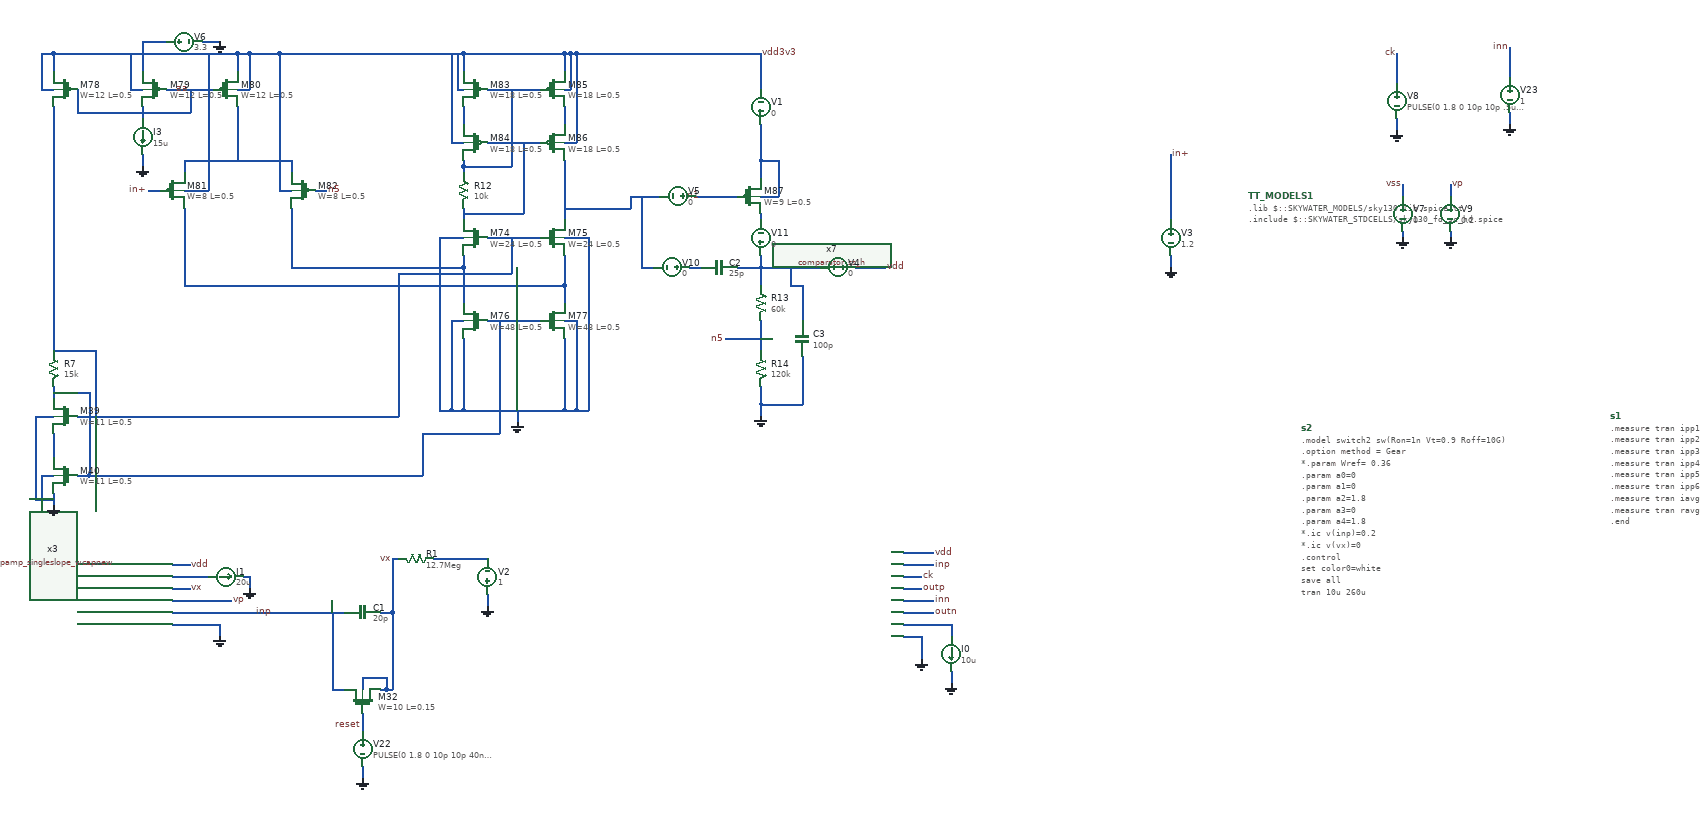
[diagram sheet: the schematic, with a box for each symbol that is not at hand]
v {xschem version=3.0.0 file_version=1.2 }
G {}
K {}
V {}
S {}
E {}
N 2980 -3130 2980 -3120 {
lab=GND}
N 2980 -3210 2980 -3190 {
lab=vp}
N 2900 -3130 2900 -3120 {
lab=GND}
N 2900 -3210 2900 -3190 {
lab=vss}
N 1180 -2490 1200 -2490 {
lab=vx}
N 1040 -2490 1120 -2490 {
lab=inp}
N 1100 -2360 1120 -2360 {
lab=inp}
N 1100 -2490 1100 -2360 {
lab=inp}
N 1180 -2360 1190 -2360 {
lab=vx}
N 1190 -2360 1200 -2360 {
lab=vx}
N 1200 -2490 1200 -2360 {
lab=vx}
N 1150 -2380 1150 -2360 {
lab=vx}
N 1150 -2380 1190 -2380 {
lab=vx}
N 1190 -2380 1190 -2360 {
lab=vx}
N 1150 -2320 1150 -2290 {
lab=reset}
N 1150 -2230 1150 -2210 {
lab=GND}
N 940 -2490 1040 -2490 {
lab=inp}
N 830 -2570 860 -2570 {
lab=vdd}
N 830 -2530 860 -2530 {
lab=vx}
N 830 -2510 910 -2510 {
lab=vp}
N 830 -2490 850 -2490 {
lab=inp}
N 830 -2470 910 -2470 {
lab=GND}
N 910 -2470 910 -2450 {
lab=GND}
N 850 -2490 940 -2490 {
lab=inp}
N 910 -2510 930 -2510 {
lab=vp}
N 960 -2550 960 -2530 {
lab=GND}
N 830 -2550 890 -2550 {
lab=#net1}
N 950 -2550 960 -2550 {
lab=GND}
N 2090 -2450 2090 -2410 {
lab=GND}
N 2060 -2570 2110 -2570 {
lab=inp}
N 2060 -2510 2110 -2510 {
lab=inn}
N 2060 -2490 2110 -2490 {
lab=outn}
N 2060 -2550 2090 -2550 {
lab=ck}
N 2060 -2530 2090 -2530 {
lab=outp}
N 2060 -2590 2110 -2590 {
lab=vdd}
N 2060 -2450 2090 -2450 {
lab=GND}
N 2140 -2470 2140 -2450 {
lab=#net2}
N 2140 -2390 2140 -2370 {
lab=GND}
N 2060 -2470 2140 -2470 {
lab=#net2}
N 2890 -3320 2890 -3300 {
lab=GND}
N 2890 -3430 2890 -3380 {
lab=ck}
N 3080 -3330 3080 -3310 {
lab=GND}
N 3080 -3440 3080 -3390 {
lab=inn}
N 2510 -3170 2510 -3150 {
lab=in+}
N 2510 -3090 2510 -3070 {
lab=GND}
N 2510 -3180 2510 -3170 {
lab=in+}
N 2510 -3190 2510 -3180 {
lab=in+}
N 2510 -3260 2510 -3250 {
lab=in+}
N 2510 -3250 2510 -3190 {
lab=in+}
N 850 -3250 850 -3230 {
lab=#net3}
N 850 -3250 1030 -3250 {
lab=#net3}
N 1030 -3250 1030 -3230 {
lab=#net3}
N 790 -3200 810 -3200 {
lab=in+}
N 1070 -3200 1090 -3200 {
lab=n5}
N 1030 -3170 1030 -3120 {
lab=#net4}
N 850 -3170 850 -3040 {
lab=#net5}
N 1030 -3070 1320 -3070 {
lab=#net4}
N 1030 -3120 1030 -3070 {
lab=#net4}
N 1490 -3090 1490 -3040 {
lab=#net5}
N 1360 -3280 1440 -3280 {
lab=#net6}
N 1440 -3280 1450 -3280 {
lab=#net6}
N 1320 -3090 1320 -3070 {
lab=#net4}
N 1360 -3120 1450 -3120 {
lab=#net7}
N 1360 -2980 1450 -2980 {
lab=#net8}
N 1320 -3070 1320 -3010 {
lab=#net4}
N 850 -3040 1490 -3040 {
lab=#net5}
N 1490 -3040 1490 -3010 {
lab=#net5}
N 1320 -2950 1320 -2930 {
lab=GND}
N 1320 -2830 1490 -2830 {
lab=GND}
N 1490 -2950 1490 -2930 {
lab=GND}
N 1410 -2830 1410 -2810 {
lab=GND}
N 1300 -2980 1320 -2980 {
lab=GND}
N 1300 -2980 1300 -2930 {
lab=GND}
N 1300 -2830 1320 -2830 {
lab=GND}
N 1490 -2980 1510 -2980 {
lab=GND}
N 1510 -2980 1510 -2930 {
lab=GND}
N 1490 -2830 1510 -2830 {
lab=GND}
N 1280 -3120 1320 -3120 {
lab=GND}
N 1280 -3120 1280 -2930 {
lab=GND}
N 1280 -2830 1300 -2830 {
lab=GND}
N 1490 -3120 1530 -3120 {
lab=GND}
N 1530 -3120 1530 -2930 {
lab=GND}
N 1510 -2830 1530 -2830 {
lab=GND}
N 1400 -3120 1400 -3060 {
lab=#net7}
N 1210 -3060 1400 -3060 {
lab=#net7}
N 1210 -3060 1210 -2880 {
lab=#net7}
N 1380 -2980 1380 -2890 {
lab=#net8}
N 1250 -2790 1380 -2790 {
lab=#net8}
N 630 -2870 630 -2850 {
lab=#net8}
N 630 -2790 630 -2750 {
lab=#net9}
N 630 -2690 630 -2670 {
lab=GND}
N 630 -2930 700 -2930 {
lab=#net7}
N 700 -2930 700 -2820 {
lab=#net7}
N 670 -2820 1210 -2820 {
lab=#net7}
N 1210 -2880 1210 -2820 {
lab=#net7}
N 630 -2860 690 -2860 {
lab=#net8}
N 690 -2860 690 -2720 {
lab=#net8}
N 670 -2720 690 -2720 {
lab=#net8}
N 690 -2720 1250 -2720 {
lab=#net8}
N 600 -2820 630 -2820 {
lab=GND}
N 600 -2820 600 -2680 {
lab=GND}
N 600 -2680 630 -2680 {
lab=GND}
N 610 -2720 630 -2720 {
lab=GND}
N 610 -2720 610 -2680 {
lab=GND}
N 630 -3230 630 -2930 {
lab=#net7}
N 820 -3370 900 -3370 {
lab=aa}
N 780 -3340 780 -3320 {
lab=aa}
N 780 -3260 780 -3240 {
lab=GND}
N 630 -3340 630 -3230 {
lab=#net7}
N 670 -3370 670 -3330 {
lab=aa}
N 860 -3370 860 -3330 {
lab=aa}
N 780 -3330 860 -3330 {
lab=aa}
N 670 -3330 780 -3330 {
lab=aa}
N 630 -3430 630 -3400 {
lab=vdd3v3}
N 630 -3430 940 -3430 {
lab=vdd3v3}
N 940 -3430 940 -3400 {
lab=vdd3v3}
N 780 -3430 780 -3400 {
lab=vdd3v3}
N 780 -3450 820 -3450 {
lab=vdd3v3}
N 880 -3450 900 -3450 {
lab=GND}
N 900 -3450 910 -3450 {
lab=GND}
N 760 -3370 780 -3370 {
lab=vdd3v3}
N 760 -3430 760 -3370 {
lab=vdd3v3}
N 610 -3370 630 -3370 {
lab=vdd3v3}
N 610 -3430 610 -3370 {
lab=vdd3v3}
N 610 -3430 630 -3430 {
lab=vdd3v3}
N 940 -3370 960 -3370 {
lab=vdd3v3}
N 960 -3430 960 -3370 {
lab=vdd3v3}
N 940 -3430 960 -3430 {
lab=vdd3v3}
N 850 -3200 890 -3200 {
lab=vdd3v3}
N 890 -3430 890 -3200 {
lab=vdd3v3}
N 1010 -3430 1010 -3200 {
lab=vdd3v3}
N 960 -3430 1010 -3430 {
lab=vdd3v3}
N 1360 -3370 1440 -3370 {
lab=#net10}
N 1440 -3370 1450 -3370 {
lab=#net10}
N 1320 -3430 1320 -3400 {
lab=vdd3v3}
N 1320 -3430 1490 -3430 {
lab=vdd3v3}
N 1490 -3430 1490 -3400 {
lab=vdd3v3}
N 1010 -3430 1320 -3430 {
lab=vdd3v3}
N 1320 -3340 1320 -3310 {
lab=#net11}
N 1490 -3340 1490 -3310 {
lab=#net12}
N 1320 -3250 1320 -3240 {
lab=#net10}
N 1400 -3370 1400 -3250 {
lab=#net10}
N 1320 -3240 1400 -3240 {
lab=#net10}
N 1400 -3250 1400 -3240 {
lab=#net10}
N 1320 -3240 1320 -3230 {
lab=#net10}
N 1320 -3170 1320 -3150 {
lab=#net6}
N 1310 -3370 1320 -3370 {
lab=vdd3v3}
N 1310 -3430 1310 -3370 {
lab=vdd3v3}
N 1490 -3370 1500 -3370 {
lab=vdd3v3}
N 1500 -3430 1500 -3370 {
lab=vdd3v3}
N 1490 -3430 1500 -3430 {
lab=vdd3v3}
N 1300 -3280 1320 -3280 {
lab=vdd3v3}
N 1300 -3430 1300 -3280 {
lab=vdd3v3}
N 1490 -3280 1510 -3280 {
lab=vdd3v3}
N 1510 -3430 1510 -3280 {
lab=vdd3v3}
N 1500 -3430 1510 -3430 {
lab=vdd3v3}
N 940 -3260 940 -3250 {
lab=#net3}
N 940 -3340 940 -3320 {
lab=#net3}
N 1250 -2790 1250 -2720 {
lab=#net8}
N 1380 -2890 1380 -2790 {
lab=#net8}
N 1280 -2930 1280 -2830 {
lab=GND}
N 1300 -2930 1300 -2830 {
lab=GND}
N 1510 -2930 1510 -2830 {
lab=GND}
N 1530 -2930 1530 -2830 {
lab=GND}
N 1320 -2930 1320 -2910 {
lab=GND}
N 1320 -2850 1320 -2830 {
lab=GND}
N 1010 -3200 1030 -3200 {
lab=vdd3v3}
N 1420 -3280 1420 -3160 {
lab=#net6}
N 1320 -3160 1420 -3160 {
lab=#net6}
N 1490 -2930 1490 -2910 {
lab=GND}
N 1490 -2850 1490 -2830 {
lab=GND}
N 1490 -3250 1490 -3240 {
lab=#net13}
N 1490 -3180 1490 -3150 {
lab=#net13}
N 1490 -3170 1600 -3170 {
lab=#net13}
N 1820 -2840 1820 -2820 {
lab=GND}
N 1820 -2980 1820 -2930 {
lab=n5}
N 1820 -3070 1820 -3040 {
lab=#net14}
N 1820 -3070 1920 -3070 {
lab=#net14}
N 1820 -2870 1820 -2840 {
lab=GND}
N 1760 -2950 1820 -2950 {
lab=n5}
N 1810 -3430 1820 -3430 {
lab=vdd3v3}
N 1820 -3190 1850 -3190 {
lab=#net15}
N 1850 -3250 1850 -3190 {
lab=#net15}
N 1820 -3250 1850 -3250 {
lab=#net15}
N 1720 -3190 1780 -3190 {
lab=n1}
N 1510 -3430 1810 -3430 {
lab=vdd3v3}
N 940 -3320 940 -3260 {
lab=#net3}
N 1490 -3240 1490 -3180 {
lab=#net13}
N 1320 -2910 1320 -2850 {
lab=GND}
N 1490 -2910 1490 -2850 {
lab=GND}
N 1600 -3190 1600 -3170 {
lab=#net13}
N 1600 -3190 1650 -3190 {
lab=#net13}
N 1780 -3070 1820 -3070 {
lab=#net14}
N 1700 -3070 1720 -3070 {
lab=#net16}
N 1980 -3070 2030 -3070 {
lab=vdd}
N 780 -3450 780 -3430 {
lab=vdd3v3}
N 1200 -2500 1200 -2490 {
lab=vx}
N 1360 -2520 1360 -2500 {
lab=GND}
N 1200 -2580 1200 -2500 {
lab=vx}
N 1270 -2580 1360 -2580 {
lab=#net17}
N 1200 -2580 1210 -2580 {
lab=vx}
N 1820 -3310 1820 -3250 {
lab=#net15}
N 1820 -3430 1820 -3370 {
lab=vdd3v3}
N 1710 -3190 1720 -3190 {
lab=n1}
N 1820 -3250 1820 -3220 {
lab=#net15}
N 1820 -3090 1820 -3070 {
lab=#net14}
N 1820 -3160 1820 -3150 {
lab=#net18}
N 1620 -3070 1640 -3070 {
lab=#net13}
N 1620 -3190 1620 -3070 {
lab=#net13}
N 1890 -3040 1890 -2980 {
lab=#net14}
N 1870 -3040 1890 -3040 {
lab=#net14}
N 1870 -3070 1870 -3040 {
lab=#net14}
N 1890 -2920 1890 -2840 {
lab=GND}
N 1820 -2840 1890 -2840 {
lab=GND}
C {devices/code_shown.sym} 2730 -2800 0 0 {name=s2 only_toplevel=false value="

.model switch2 sw(Ron=1n Vt=0.9 Roff=10G)
.option method = Gear
*.param Wref= 0.36
.param a0=0
.param a1=0
.param a2=1.8
.param a3=0
.param a4=1.8
*.ic v(inp)=0.2
*.ic v(vx)=0


.control
set color0=white
save all

tran 10u 260u
plot inp inn outp outn
plot inp_neg inn outp_neg outn_neg
let i_1v8 = i(v4)
let i_3v3 = i(v6)
let i_g= i(v5)
let i_miller = i(v10)
let i_s= i(v1)
let i_d = i(v11)
let zort = vdd/i(v4)
plot i_1v8 i_3v3
plot v(vdd)
plot vdd3v3
plot i_1v8
plot i_3v3
plot i_g
plot i_miller
plot i_d
plot i_s
*show all
.endc
.end
"
}
C {devices/code.sym} 2640 -3190 0 0 {name=TT_MODELS1
only_toplevel=true
format="tcleval(@value )"
value=".lib $::SKYWATER_MODELS/sky130.lib.spice tt
.include $::SKYWATER_STDCELLS/sky130_fd_sc_hd.spice
"
spice_ignore=false
place=header}
C {devices/vsource.sym} 2980 -3160 0 0 {name=V9 value=0.2}
C {devices/gnd.sym} 2980 -3120 0 1 {name=l5 lab=GND}
C {devices/vsource.sym} 2900 -3160 0 0 {name=V7 value=0}
C {devices/gnd.sym} 2900 -3120 0 1 {name=l53 lab=GND}
C {devices/lab_pin.sym} 2900 -3210 0 0 {name=l54 sig_type=std_logic lab=vss}
C {devices/lab_pin.sym} 2980 -3210 2 0 {name=l59 sig_type=std_logic lab=vp}
C {devices/capa.sym} 1150 -2490 1 0 {name=C1
m=1
value=20p
footprint=1206
device="ceramic capacitor"}
C {pdk/sky130A/libs.tech/xschem/sky130_fd_pr/nfet_01v8.sym} 1150 -2340 3 0 {name=M32
L=0.15
W=10
nf=1 
mult=2
ad="'int((nf+1)/2) * W/nf * 0.29'" 
pd="'2*int((nf+1)/2) * (W/nf + 0.29)'"
as="'int((nf+2)/2) * W/nf * 0.29'" 
ps="'2*int((nf+2)/2) * (W/nf + 0.29)'"
nrd="'0.29 / W'" nrs="'0.29 / W'"
sa=0 sb=0 sd=0
model=nfet_01v8
spiceprefix=X
}
C {devices/vsource.sym} 1150 -2260 0 0 {name=V22 value="PULSE(0 1.8 0 10p 10p 40n 256.04u)"}
C {devices/gnd.sym} 1150 -2210 0 0 {name=l81 lab=GND}
C {devices/lab_pin.sym} 860 -2570 2 0 {name=l82 sig_type=std_logic lab=vdd}
C {devices/lab_pin.sym} 1150 -2300 0 0 {name=l83 sig_type=std_logic lab=reset}
C {devices/lab_pin.sym} 860 -2530 2 0 {name=l84 sig_type=std_logic lab=vx}
C {devices/gnd.sym} 910 -2450 0 0 {name=l85 lab=GND}
C {devices/lab_pin.sym} 1000 -2490 1 0 {name=l86 sig_type=std_logic lab=inp}
C {devices/isource.sym} 920 -2550 3 0 {name=I1 value=20u}
C {devices/gnd.sym} 960 -2530 0 0 {name=l87 lab=GND}
C {design/single_slope/opamp_singleslope_wcapnew.sym} 680 -2520 0 0 {name=x3}
C {devices/lab_pin.sym} 930 -2510 0 1 {name=l88 sig_type=std_logic lab=vp}
C {devices/gnd.sym} 2090 -2410 0 0 {name=l76 lab=GND}
C {devices/lab_pin.sym} 2110 -2590 0 1 {name=l79 sig_type=std_logic lab=vdd}
C {devices/lab_pin.sym} 2090 -2550 0 1 {name=l107 sig_type=std_logic lab=ck}
C {devices/lab_pin.sym} 2110 -2570 0 1 {name=l108 sig_type=std_logic lab=inp}
C {devices/lab_pin.sym} 2110 -2510 0 1 {name=l109 sig_type=std_logic lab=inn}
C {devices/lab_pin.sym} 2090 -2530 0 1 {name=l110 sig_type=std_logic lab=outp}
C {devices/lab_pin.sym} 2110 -2490 0 1 {name=l111 sig_type=std_logic lab=outn}
C {devices/isource.sym} 2140 -2420 0 0 {name=I0 value=10u}
C {devices/gnd.sym} 2140 -2370 0 0 {name=l112 lab=GND}
C {design/single_slope/comparator_ss_h.sym} 1910 -2520 0 0 {name=x7}
C {devices/vsource.sym} 2890 -3350 0 0 {name=V8 value="PULSE(0 1.8 0 10p 10p .5u 1u)"
}
C {devices/gnd.sym} 2890 -3300 0 0 {name=l123 lab=GND}
C {devices/lab_pin.sym} 2890 -3430 0 0 {name=l124 sig_type=std_logic lab=ck}
C {devices/vsource.sym} 3080 -3360 0 0 {name=V23 value=1}
C {devices/gnd.sym} 3080 -3310 0 0 {name=l125 lab=GND}
C {devices/lab_pin.sym} 3080 -3440 0 0 {name=l126 sig_type=std_logic lab=inn}
C {devices/vsource.sym} 2510 -3120 0 0 {name=V3 value=1.2}
C {devices/gnd.sym} 2510 -3070 0 0 {name=l4 lab=GND}
C {devices/lab_pin.sym} 2510 -3260 2 0 {name=l24 sig_type=std_logic lab=in+}
C {devices/lab_pin.sym} 790 -3200 0 0 {name=l25 sig_type=std_logic lab=in+}
C {devices/gnd.sym} 1410 -2810 0 0 {name=l26 lab=GND}
C {devices/res.sym} 630 -2900 0 0 {name=R7
value=15k
footprint=1206
device=resistor
m=1}
C {devices/gnd.sym} 630 -2670 0 0 {name=l134 lab=GND}
C {devices/isource.sym} 780 -3290 0 0 {name=I3 value=15u}
C {devices/gnd.sym} 780 -3240 0 0 {name=l97 lab=GND}
C {devices/vsource.sym} 850 -3450 3 0 {name=V6 value=3.3}
C {devices/gnd.sym} 910 -3450 0 0 {name=l98 lab=GND}
C {devices/lab_pin.sym} 860 -3370 1 0 {name=l99 sig_type=std_logic lab=aa}
C {devices/res.sym} 1320 -3200 0 0 {name=R12
value=10k
footprint=1206
device=resistor
m=1}
C {pdk/sky130A/libs.tech/xschem/sky130_fd_pr/nfet_01v8.sym} 650 -2820 0 1 {name=M39
L=0.5
W=11
nf=1 
mult=1
ad="'int((nf+1)/2) * W/nf * 0.29'" 
pd="'2*int((nf+1)/2) * (W/nf + 0.29)'"
as="'int((nf+2)/2) * W/nf * 0.29'" 
ps="'2*int((nf+2)/2) * (W/nf + 0.29)'"
nrd="'0.29 / W'" nrs="'0.29 / W'"
sa=0 sb=0 sd=0
model=nfet_01v8
spiceprefix=X
}
C {pdk/sky130A/libs.tech/xschem/sky130_fd_pr/nfet_01v8.sym} 650 -2720 0 1 {name=M40
L=0.5
W=11
nf=1 
mult=1
ad="'int((nf+1)/2) * W/nf * 0.29'" 
pd="'2*int((nf+1)/2) * (W/nf + 0.29)'"
as="'int((nf+2)/2) * W/nf * 0.29'" 
ps="'2*int((nf+2)/2) * (W/nf + 0.29)'"
nrd="'0.29 / W'" nrs="'0.29 / W'"
sa=0 sb=0 sd=0
model=nfet_01v8
spiceprefix=X
}
C {pdk/sky130A/libs.tech/xschem/sky130_fd_pr/nfet_01v8.sym} 1340 -3120 0 1 {name=M74
L=0.5
W=24
nf=4
mult=1
ad="'int((nf+1)/2) * W/nf * 0.29'" 
pd="'2*int((nf+1)/2) * (W/nf + 0.29)'"
as="'int((nf+2)/2) * W/nf * 0.29'" 
ps="'2*int((nf+2)/2) * (W/nf + 0.29)'"
nrd="'0.29 / W'" nrs="'0.29 / W'"
sa=0 sb=0 sd=0
model=nfet_01v8
spiceprefix=X
}
C {pdk/sky130A/libs.tech/xschem/sky130_fd_pr/nfet_01v8.sym} 1470 -3120 0 0 {name=M75
L=0.5
W=24
nf=4 
mult=1
ad="'int((nf+1)/2) * W/nf * 0.29'" 
pd="'2*int((nf+1)/2) * (W/nf + 0.29)'"
as="'int((nf+2)/2) * W/nf * 0.29'" 
ps="'2*int((nf+2)/2) * (W/nf + 0.29)'"
nrd="'0.29 / W'" nrs="'0.29 / W'"
sa=0 sb=0 sd=0
model=nfet_01v8
spiceprefix=X
}
C {pdk/sky130A/libs.tech/xschem/sky130_fd_pr/nfet_01v8.sym} 1340 -2980 0 1 {name=M76
L=0.5
W=48
nf=8
mult=1
ad="'int((nf+1)/2) * W/nf * 0.29'" 
pd="'2*int((nf+1)/2) * (W/nf + 0.29)'"
as="'int((nf+2)/2) * W/nf * 0.29'" 
ps="'2*int((nf+2)/2) * (W/nf + 0.29)'"
nrd="'0.29 / W'" nrs="'0.29 / W'"
sa=0 sb=0 sd=0
model=nfet_01v8
spiceprefix=X
}
C {pdk/sky130A/libs.tech/xschem/sky130_fd_pr/nfet_01v8.sym} 1470 -2980 0 0 {name=M77
L=0.5
W=48
nf=8
mult=1
ad="'int((nf+1)/2) * W/nf * 0.29'" 
pd="'2*int((nf+1)/2) * (W/nf + 0.29)'"
as="'int((nf+2)/2) * W/nf * 0.29'" 
ps="'2*int((nf+2)/2) * (W/nf + 0.29)'"
nrd="'0.29 / W'" nrs="'0.29 / W'"
sa=0 sb=0 sd=0
model=nfet_01v8
spiceprefix=X
}
C {pdk/sky130A/libs.tech/xschem/sky130_fd_pr/pfet_g5v0d10v5.sym} 650 -3370 0 1 {name=M78
L=0.5
W=12
nf=1
mult=2
ad="'int((nf+1)/2) * W/nf * 0.29'" 
pd="'2*int((nf+1)/2) * (W/nf + 0.29)'"
as="'int((nf+2)/2) * W/nf * 0.29'" 
ps="'2*int((nf+2)/2) * (W/nf + 0.29)'"
nrd="'0.29 / W'" nrs="'0.29 / W'"
sa=0 sb=0 sd=0
model=pfet_g5v0d10v5
spiceprefix=X
}
C {pdk/sky130A/libs.tech/xschem/sky130_fd_pr/pfet_g5v0d10v5.sym} 800 -3370 0 1 {name=M79
L=0.5
W=12
nf=1
mult=1
ad="'int((nf+1)/2) * W/nf * 0.29'" 
pd="'2*int((nf+1)/2) * (W/nf + 0.29)'"
as="'int((nf+2)/2) * W/nf * 0.29'" 
ps="'2*int((nf+2)/2) * (W/nf + 0.29)'"
nrd="'0.29 / W'" nrs="'0.29 / W'"
sa=0 sb=0 sd=0
model=pfet_g5v0d10v5
spiceprefix=X
}
C {pdk/sky130A/libs.tech/xschem/sky130_fd_pr/pfet_g5v0d10v5.sym} 920 -3370 0 0 {name=M80
L=0.5
W=12
nf=1
mult=10
ad="'int((nf+1)/2) * W/nf * 0.29'" 
pd="'2*int((nf+1)/2) * (W/nf + 0.29)'"
as="'int((nf+2)/2) * W/nf * 0.29'" 
ps="'2*int((nf+2)/2) * (W/nf + 0.29)'"
nrd="'0.29 / W'" nrs="'0.29 / W'"
sa=0 sb=0 sd=0
model=pfet_g5v0d10v5
spiceprefix=X
}
C {pdk/sky130A/libs.tech/xschem/sky130_fd_pr/pfet_g5v0d10v5.sym} 830 -3200 0 0 {name=M81
L=0.5
W=8
nf=1
mult=10
ad="'int((nf+1)/2) * W/nf * 0.29'" 
pd="'2*int((nf+1)/2) * (W/nf + 0.29)'"
as="'int((nf+2)/2) * W/nf * 0.29'" 
ps="'2*int((nf+2)/2) * (W/nf + 0.29)'"
nrd="'0.29 / W'" nrs="'0.29 / W'"
sa=0 sb=0 sd=0
model=pfet_g5v0d10v5
spiceprefix=X
}
C {pdk/sky130A/libs.tech/xschem/sky130_fd_pr/pfet_g5v0d10v5.sym} 1050 -3200 0 1 {name=M82
L=0.5
W=8
nf=1
mult=10
ad="'int((nf+1)/2) * W/nf * 0.29'" 
pd="'2*int((nf+1)/2) * (W/nf + 0.29)'"
as="'int((nf+2)/2) * W/nf * 0.29'" 
ps="'2*int((nf+2)/2) * (W/nf + 0.29)'"
nrd="'0.29 / W'" nrs="'0.29 / W'"
sa=0 sb=0 sd=0
model=pfet_g5v0d10v5
spiceprefix=X
}
C {pdk/sky130A/libs.tech/xschem/sky130_fd_pr/pfet_g5v0d10v5.sym} 1340 -3370 0 1 {name=M83
L=0.5
W=18
nf=2
mult=1
ad="'int((nf+1)/2) * W/nf * 0.29'" 
pd="'2*int((nf+1)/2) * (W/nf + 0.29)'"
as="'int((nf+2)/2) * W/nf * 0.29'" 
ps="'2*int((nf+2)/2) * (W/nf + 0.29)'"
nrd="'0.29 / W'" nrs="'0.29 / W'"
sa=0 sb=0 sd=0
model=pfet_g5v0d10v5
spiceprefix=X
}
C {pdk/sky130A/libs.tech/xschem/sky130_fd_pr/pfet_g5v0d10v5.sym} 1340 -3280 0 1 {name=M84
L=0.5
W=18
nf=2
mult=1
ad="'int((nf+1)/2) * W/nf * 0.29'" 
pd="'2*int((nf+1)/2) * (W/nf + 0.29)'"
as="'int((nf+2)/2) * W/nf * 0.29'" 
ps="'2*int((nf+2)/2) * (W/nf + 0.29)'"
nrd="'0.29 / W'" nrs="'0.29 / W'"
sa=0 sb=0 sd=0
model=pfet_g5v0d10v5
spiceprefix=X
}
C {pdk/sky130A/libs.tech/xschem/sky130_fd_pr/pfet_g5v0d10v5.sym} 1470 -3370 0 0 {name=M85
L=0.5
W=18
nf=2
mult=1
ad="'int((nf+1)/2) * W/nf * 0.29'" 
pd="'2*int((nf+1)/2) * (W/nf + 0.29)'"
as="'int((nf+2)/2) * W/nf * 0.29'" 
ps="'2*int((nf+2)/2) * (W/nf + 0.29)'"
nrd="'0.29 / W'" nrs="'0.29 / W'"
sa=0 sb=0 sd=0
model=pfet_g5v0d10v5
spiceprefix=X
}
C {pdk/sky130A/libs.tech/xschem/sky130_fd_pr/pfet_g5v0d10v5.sym} 1470 -3280 0 0 {name=M86
L=0.5
W=18
nf=2
mult=1
ad="'int((nf+1)/2) * W/nf * 0.29'" 
pd="'2*int((nf+1)/2) * (W/nf + 0.29)'"
as="'int((nf+2)/2) * W/nf * 0.29'" 
ps="'2*int((nf+2)/2) * (W/nf + 0.29)'"
nrd="'0.29 / W'" nrs="'0.29 / W'"
sa=0 sb=0 sd=0
model=pfet_g5v0d10v5
spiceprefix=X
}
C {devices/gnd.sym} 1820 -2820 0 0 {name=l156 lab=GND}
C {devices/res.sym} 1820 -3010 0 0 {name=R13
value=60k
footprint=1206
device=resistor
m=1}
C {devices/res.sym} 1820 -2900 0 0 {name=R14
value=120k
footprint=1206
device=resistor
m=1}
C {devices/lab_pin.sym} 1760 -2950 0 0 {name=l100 sig_type=std_logic lab=n5}
C {pdk/sky130A/libs.tech/xschem/sky130_fd_pr/pfet_g5v0d10v5.sym} 1800 -3190 0 0 {name=M87
L=0.5
W=9
nf=1
mult=30
ad="'int((nf+1)/2) * W/nf * 0.29'" 
pd="'2*int((nf+1)/2) * (W/nf + 0.29)'"
as="'int((nf+2)/2) * W/nf * 0.29'" 
ps="'2*int((nf+2)/2) * (W/nf + 0.29)'"
nrd="'0.29 / W'" nrs="'0.29 / W'"
sa=0 sb=0 sd=0
model=pfet_g5v0d10v5
spiceprefix=X
}
C {devices/lab_pin.sym} 1720 -3190 1 1 {name=l159 sig_type=std_logic lab=n1}
C {devices/lab_pin.sym} 1820 -3430 0 1 {name=l160 sig_type=std_logic lab=vdd3v3}
C {devices/lab_pin.sym} 1090 -3200 0 1 {name=l161 sig_type=std_logic lab=n5}
C {devices/capa.sym} 1750 -3070 3 0 {name=C2
m=1
value=25p
footprint=1206
device="ceramic capacitor"}
C {devices/lab_pin.sym} 2030 -3070 0 1 {name=l101 sig_type=std_logic lab=vdd}
C {devices/vsource.sym} 1950 -3070 1 0 {name=V4 value=0}
C {devices/vsource.sym} 1360 -2550 2 0 {name=V2 value=1}
C {devices/gnd.sym} 1360 -2500 0 0 {name=l1 lab=GND}
C {devices/res.sym} 1240 -2580 1 0 {name=R1
value=12.7Meg
footprint=1206
device=resistor
m=1}
C {devices/lab_pin.sym} 1200 -2580 1 0 {name=l6 sig_type=std_logic lab=vx}
C {devices/vsource.sym} 1820 -3340 2 0 {name=V1 value=0}
C {devices/vsource.sym} 1680 -3190 1 0 {name=V5 value=0}
C {devices/vsource.sym} 1670 -3070 1 0 {name=V10 value=0}
C {devices/vsource.sym} 1820 -3120 2 0 {name=V11 value=0}
C {devices/code_shown.sym} 3250 -2820 0 0 {name=s1 only_toplevel=false value="

.measure tran ipp1 PP i(v6) from=5u to=6u
.measure tran ipp2 PP i(v6) from=20u to=21u
.measure tran ipp3 PP i(v6) from=50u to=51u
.measure tran ipp4 PP i(v6) from=100u to=101u
.measure tran ipp5 PP i(v6) from=170u to=171u
.measure tran ipp6 PP i(v6) from=220u to=221u
.measure tran iavg AVG i(v4) from=1u to=255u
.measure tran ravg AVG zort from=1u to=255u
.end
"
}
C {devices/capa.sym} 1890 -2950 0 0 {name=C3
m=1
value=100p
footprint=1206
device="ceramic capacitor"}
